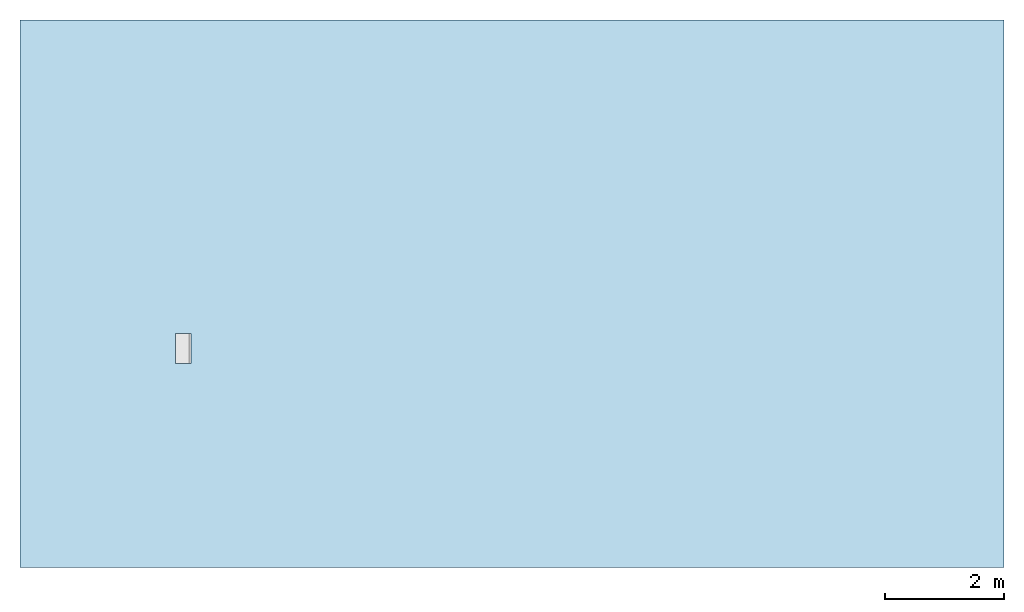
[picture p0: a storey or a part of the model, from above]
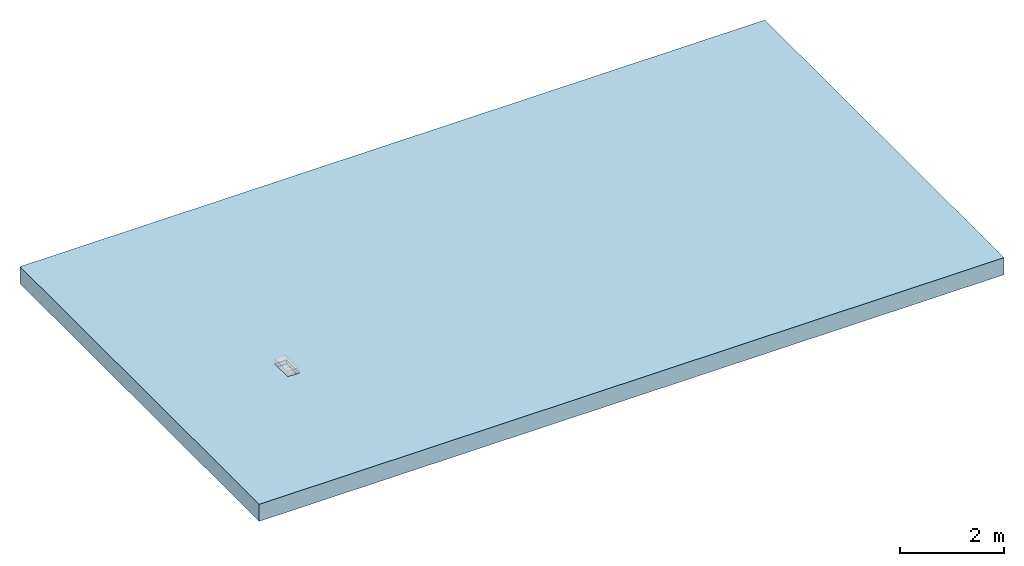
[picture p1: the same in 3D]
Properties of the parts of a building model (IFC2X3)

# File
Description: ViewDefinition [CoordinationView]
File name: T0129 - Access unit - 500mm LG - 220mm High.ifc
Time: 2013-09-04T09:00:32
Written by: Autodesk Revit 2013
Made in: 20120221_2030(x64)

# IfcProject, Project Number
LongName: Project Name; Phase: Project Status

# IfcSite, Default
RefLatitude: 42, 21, 30, 344238; RefLongitude: -71, -3, -35, -194702; RefElevation: 0 mm

# IfcBuilding
Pset_BuildingCommon - NumberOfStoreys: 1
Other - Project Number: Project Number; Project Issue Date: Issue Date; Client Name: Owner; Project Name: Project Name; Project Address: ## Street City, State Zip; Project Status: Project Status

# IfcBuildingStorey, Level 1
LongName: Level 1; Elevation: 0 mm
Constraints - Elevation Base: 0; Elevation: 0 mm
Graphics - Symbol: M_Level Head - Circle: M_Level Head - Circle; Line Pattern: Center; Line Weight: 1; Color: 0; Symbol at End 2 Default: yes; Symbol at End 1 Default: no
Identity Data - Building Story: yes; Structural: no; Name: Level 1
Dimensions - Computation Height: 0 mm

# IfcBuildingElementProxy: T0129 - Access unit - 500mm LG - 220mm High, Civil-Drainage-Channel-ACO-KerbDrain-KD200:T0129 - Access unit - 500mm LG - 220mm High:T0129 - Access unit - 500mm LG - 220mm High:308203
In: Level 1
Material: ACO Polymer Concrete., Iron, Cast
Constraints - Moves With Nearby Elements: no; Level: Level: Level 1
Phasing - Phase Created: New Construction
Dimensions - Volume: 19007850 mm3; Void Depth.: -95 mm; Void length: 500 mm
Pset_BuildingElementProxyCommon - Reference: T0129 - Access unit - 500mm LG - 220mm High
Identity Data - Assembly Code: D2040; Price: POA - contact ACO; URL: www.aco.co.uk; Manufacturer: ACO Technologies plc - ACO Water Management Division; Product Page URL: http://www.aco.co.uk/product_detail.php?id=3; Telephone: +44 (0)1462 816666; Model: ACO KerbDrain KD200; Maintenance guidelines: http://www.aco.co.uk/download.php?id=120; Installation guidelines: http://www.aco.co.uk/download.php?id=120; OmniClass Number: 23.70.50.24; Cost: 0; Product brochure: http://www.aco.co.uk/download.php?id=120; e-mail Sales: customersupport@aco.co.uk; Fax: +44 (0)1462 815895; Model Description: Combined kerb and drainage system; e-mail Technical: technical@aco.co.uk; Product Code: T0129; OmniClass Title: Rainwater Removal; Type Comments: ACO KerbDrain KD200 half battered rodding access unit 220mm high 500mm long; Address: ACO Business Park, Hitchin Road, Shefford, Bedfordshire, United Kingdom SG17 5TE; Assembly Description: Rain Water Drainage
General - SerialNumber: 0.000000; TagNumber: 0.000000
Green Building Properties - End Cap Recycled Material Content: N/A; End Cap Recyclable: N/A; Access Cover/Frame Recycled Material Content: Between 40% - 90%; Channel Recyclable: Fully recyclable; Access Cover/Frame Recyclable: Fully recyclable; Channel Recycled Material Content: 20% minimum
Data - Channel C.S.A: 0.02m²; Product Dimensions: 500mm x 260mm x 220mm (LxWxH); Concrete Surround Volume - Load Class A 15 - D 400 - Concrete Pavement: 0.20m³/m; Load Class: A 15 - D 400; Hydraulic Performance: http://www.aco.co.uk/download.php?id=120; Drainage Slot Width: N/A; ACO Hydraulic Design Software: http://www.acodesign.co.uk; Invert Depth: 190mm; Product Standard: BS EN 1433:2002, CE marked, Kitemarked; Installation - Concrete Grade: Refer to brochure; Product Weight: 41.5 Kg; Drainage Slot Intake area: N/A
Other - CreatedBy: www.aco.co.uk; Revision: 1
Construction - Closing end cap: no; Accessunit_235: no; Blindunit_235: no; Access Cover: yes; Blindunit_220: no; Channelunit_220: no; Accessunit_220: yes; Channelunit_235: no
Materials and Finishes - Channel Colour: Grey; End Cap Colour: N/A; Channel Material: Vienite® Synthetic Resin Concrete; Access Cover/Frame Colour: Black; Access Cover/Frame Material: Ductile Iron; Access Cover/Frame Finish: Water Based Paint Coating; End Cap Material: N/A

# IfcOpeningElement: Recess
In: Level 1
Dimensions - Thickness: 400 mm; Perimeter: 51360 mm; Area: 151470000 mm2; Volume: 60575650000 mm3
Constraints - Level: Level: Level 1; Room Bounding: yes; Height Offset From Level: 0 mm; Related to Mass: no
Phasing - Phase Created: New Construction
Structural - Structural: no; Enable Analytical Model: no
Analytical Properties - Roughness: 1; Absorptance: 0.1
Construction - Function: 0; Default Thickness: 400 mm
Graphics - Coarse Scale Fill Color: 0
Materials and Finishes - Structural Material: Plant

# IfcSlab: Floor:Generic Floor - 400mm, Floor:Generic Floor - 400mm:193825
In: Level 1
PredefinedType: FLOOR; Material: Plant 400 mm
Dimensions - Thickness: 400 mm; Perimeter: 51360 mm; Area: 151470000 mm2; Volume: 60575650000 mm3
Constraints - Level: Level: Level 1; Room Bounding: yes; Height Offset From Level: 0 mm; Related to Mass: no
Phasing - Phase Created: New Construction
Structural - Structural: no; Enable Analytical Model: no
Pset_SlabCommon - Reference: Generic Floor - 400mm; IsExternal: no; LoadBearing: yes
Analytical Properties - Roughness: 1; Absorptance: 0.1
Construction - Function: 0; Default Thickness: 400 mm
Graphics - Coarse Scale Fill Color: 0
Materials and Finishes - Structural Material: Plant
